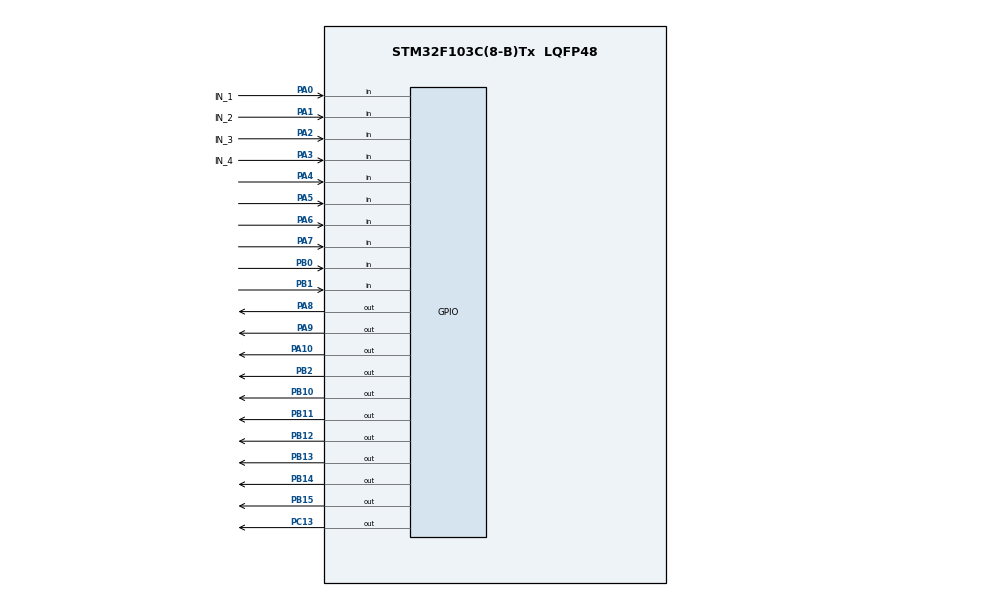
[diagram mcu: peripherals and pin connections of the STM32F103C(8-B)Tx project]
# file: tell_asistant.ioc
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Mcu.Family=STM32F1
Mcu.Name=STM32F103C(8-B)Tx
Mcu.Package=LQFP48
NVIC.PriorityGroup=NVIC_PRIORITYGROUP_4
NVIC.TIM4_IRQn=true\:0\:0\:false\:false\:true\:true
PA0-WKUP.GPIO_Label=IN_1
PA0-WKUP.GPIO_Mode=GPIO_MODE_INPUT
PA0-WKUP.GPIO_PuPd=GPIO_PULLUP
PA0-WKUP.Signal=GPIO_Input
PA1.GPIO_Label=IN_2
PA1.GPIO_Mode=GPIO_MODE_INPUT
PA1.GPIO_PuPd=GPIO_PULLUP
PA1.Signal=GPIO_Input
PA10.Signal=GPIO_Output
PA13.Mode=Serial_Wire
PA13.Signal=SYS_JTMS-SWDIO
PA14.Mode=Serial_Wire
PA14.Signal=SYS_JTCK-SWCLK
PA2.GPIO_Label=IN_3
PA2.GPIO_Mode=GPIO_MODE_INPUT
PA2.GPIO_PuPd=GPIO_PULLUP
PA2.Signal=GPIO_Input
PA3.GPIO_Label=IN_4
PA3.GPIO_Mode=GPIO_MODE_INPUT
PA3.GPIO_PuPd=GPIO_PULLUP
PA3.Signal=GPIO_Input
PA4.Signal=GPIO_Input
PA5.Signal=GPIO_Input
PA6.Signal=GPIO_Input
PA7.Signal=GPIO_Input
PA8.Signal=GPIO_Output
PA9.Signal=GPIO_Output
PB0.Signal=GPIO_Input
PB1.Signal=GPIO_Input
PB10.Signal=GPIO_Output
PB11.Signal=GPIO_Output
PB12.Signal=GPIO_Output
PB13.Signal=GPIO_Output
PB14.Signal=GPIO_Output
PB15.Signal=GPIO_Output
PB2.Signal=GPIO_Output
PC13-TAMPER-RTC.Signal=GPIO_Output
ProjectManager.HeapSize=0x200
ProjectManager.StackSize=0x400
ProjectManager.TargetToolchain=MDK-ARM V5
RCC.APB1Freq_Value=8000000
RCC.APB2Freq_Value=8000000
TIM4.AutoReloadPreload=TIM_AUTORELOAD_PRELOAD_ENABLE
TIM4.Period=1000
TIM4.Prescaler=8000
VP_TIM4_VS_ClockSourceINT.Mode=Internal
board=custom

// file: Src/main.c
/* USER CODE BEGIN Header */
/**
  ******************************************************************************
  * @file           : main.c
  * @brief          : Main program body
  ******************************************************************************
  ** This notice applies to any and all portions of this file
  * that are not between comment pairs USER CODE BEGIN and
  * USER CODE END. Other portions of this file, whether
  * inserted by the user or by software development tools
  * are owned by their respective copyright owners.
  *
  * COPYRIGHT(c) 2020 STMicroelectronics
  *
  * Redistribution and use in source and binary forms, with or without modification,
  * are permitted provided that the following conditions are met:
  *   1. Redistributions of source code must retain the above copyright notice,
  *      this list of conditions and the following disclaimer.
  *   2. Redistributions in binary form must reproduce the above copyright notice,
  *      this list of conditions and the following disclaimer in the documentation
  *      and/or other materials provided with the distribution.
  *   3. Neither the name of STMicroelectronics nor the names of its contributors
  *      may be used to endorse or promote products derived from this software
  *      without specific prior written permission.
  *
  * THIS SOFTWARE IS PROVIDED BY THE COPYRIGHT HOLDERS AND CONTRIBUTORS "AS IS"
  * AND ANY EXPRESS OR IMPLIED WARRANTIES, INCLUDING, BUT NOT LIMITED TO, THE
  * IMPLIED WARRANTIES OF MERCHANTABILITY AND FITNESS FOR A PARTICULAR PURPOSE ARE
  * DISCLAIMED. IN NO EVENT SHALL THE COPYRIGHT HOLDER OR CONTRIBUTORS BE LIABLE
  * FOR ANY DIRECT, INDIRECT, INCIDENTAL, SPECIAL, EXEMPLARY, OR CONSEQUENTIAL
  * DAMAGES (INCLUDING, BUT NOT LIMITED TO, PROCUREMENT OF SUBSTITUTE GOODS OR
  * SERVICES; LOSS OF USE, DATA, OR PROFITS; OR BUSINESS INTERRUPTION) HOWEVER
  * CAUSED AND ON ANY THEORY OF LIABILITY, WHETHER IN CONTRACT, STRICT LIABILITY,
  * OR TORT (INCLUDING NEGLIGENCE OR OTHERWISE) ARISING IN ANY WAY OUT OF THE USE
  * OF THIS SOFTWARE, EVEN IF ADVISED OF THE POSSIBILITY OF SUCH DAMAGE.
  *
  ******************************************************************************
  */
/* USER CODE END Header */

#include "main.h"

/* USER CODE BEGIN Includes */

#define led1(x) (x)?   HAL_GPIO_WritePin(OUT1_GPIO_Port,OUT1_Pin,GPIO_PIN_SET) :  HAL_GPIO_WritePin(OUT1_GPIO_Port,OUT1_Pin,GPIO_PIN_RESET)
#define led2(x) (x)?   HAL_GPIO_WritePin(OUT2_GPIO_Port,OUT2_Pin,GPIO_PIN_SET) :  HAL_GPIO_WritePin(OUT2_GPIO_Port,OUT2_Pin,GPIO_PIN_RESET)
#define led3(x) (x)?   HAL_GPIO_WritePin(OUT3_GPIO_Port,OUT3_Pin,GPIO_PIN_SET) :  HAL_GPIO_WritePin(OUT3_GPIO_Port,OUT3_Pin,GPIO_PIN_RESET)
#define led4(x) (x)?   HAL_GPIO_WritePin(OUT4_GPIO_Port,OUT4_Pin,GPIO_PIN_SET) :  HAL_GPIO_WritePin(OUT4_GPIO_Port,OUT4_Pin,GPIO_PIN_RESET)

#define in1  !HAL_GPIO_ReadPin( IN_1_GPIO_Port,IN_1_Pin )
#define in2  !HAL_GPIO_ReadPin( IN_2_GPIO_Port,IN_2_Pin )
#define in3  !HAL_GPIO_ReadPin( IN_3_GPIO_Port,IN_3_Pin )
#define in4  !HAL_GPIO_ReadPin( IN_4_GPIO_Port,IN_4_Pin )

 #define defult_time  10
/* USER CODE END Includes */

/* USER CODE BEGIN PTD */

struct TIMEING {

	public:
	int time_out_1 ;
	int time_out_2 ;
	int time_out_3 ;
	int time_out_4 ;

}tim;

struct flag
	{
	  bool flag_out_1;
	  bool flag_out_2;
	  bool flag_out_3;
	  bool flag_out_4;

  }fl;

/* USER CODE END PTD */

TIM_HandleTypeDef htim4;

void SystemClock_Config(void);
static void MX_GPIO_Init(void);
static void MX_TIM4_Init(void);

int main(void)
{

  /* MCU Configuration--------------------------------------------------------*/

  /* Reset of all peripherals, Initializes the Flash interface and the Systick. */
  HAL_Init();

  /* Configure the system clock */
  SystemClock_Config();

  /* Initialize all configured peripherals */
  MX_GPIO_Init();
  MX_TIM4_Init();
  /* USER CODE BEGIN 2 */
  HAL_TIM_Base_Start_IT(&htim4);
  /* USER CODE END 2 */

  /* Infinite loop */
  /* USER CODE BEGIN WHILE */

  while (1)
  {

		 led1( tim.time_out_1);
		 led2( tim.time_out_2);
		 led3( tim.time_out_3);
		 led4( tim.time_out_4);

		if(in1) tim.time_out_1 = defult_time;
		if(in2) tim.time_out_2 = defult_time;
		if(in3) tim.time_out_3 = defult_time;
		if(in4) tim.time_out_4 = defult_time;

    /* USER CODE END WHILE */

  }
}

void SystemClock_Config(void)
{
  RCC_OscInitTypeDef RCC_OscInitStruct = {0};
  RCC_ClkInitTypeDef RCC_ClkInitStruct = {0};

  /**Initializes the CPU, AHB and APB busses clocks
  */
  RCC_OscInitStruct.OscillatorType = RCC_OSCILLATORTYPE_HSI;
  RCC_OscInitStruct.HSIState = RCC_HSI_ON;
  RCC_OscInitStruct.HSICalibrationValue = RCC_HSICALIBRATION_DEFAULT;
  RCC_OscInitStruct.PLL.PLLState = RCC_PLL_NONE;
  if (HAL_RCC_OscConfig(&RCC_OscInitStruct) != HAL_OK)
  {
    Error_Handler();
  }
  /**Initializes the CPU, AHB and APB busses clocks
  */
  RCC_ClkInitStruct.ClockType = RCC_CLOCKTYPE_HCLK|RCC_CLOCKTYPE_SYSCLK
                              |RCC_CLOCKTYPE_PCLK1|RCC_CLOCKTYPE_PCLK2;
  RCC_ClkInitStruct.SYSCLKSource = RCC_SYSCLKSOURCE_HSI;
  RCC_ClkInitStruct.AHBCLKDivider = RCC_SYSCLK_DIV1;
  RCC_ClkInitStruct.APB1CLKDivider = RCC_HCLK_DIV1;
  RCC_ClkInitStruct.APB2CLKDivider = RCC_HCLK_DIV1;

  if (HAL_RCC_ClockConfig(&RCC_ClkInitStruct, FLASH_LATENCY_0) != HAL_OK)
  {
    Error_Handler();
  }
}

static void MX_TIM4_Init(void)
{

  TIM_ClockConfigTypeDef sClockSourceConfig = {0};
  TIM_MasterConfigTypeDef sMasterConfig = {0};

  htim4.Instance = TIM4;
  htim4.Init.Prescaler = 8000;
  htim4.Init.CounterMode = TIM_COUNTERMODE_UP;
  htim4.Init.Period = 1000;
  htim4.Init.ClockDivision = TIM_CLOCKDIVISION_DIV1;
  htim4.Init.AutoReloadPreload = TIM_AUTORELOAD_PRELOAD_ENABLE;
  if (HAL_TIM_Base_Init(&htim4) != HAL_OK)
  {
    Error_Handler();
  }
  sClockSourceConfig.ClockSource = TIM_CLOCKSOURCE_INTERNAL;
  if (HAL_TIM_ConfigClockSource(&htim4, &sClockSourceConfig) != HAL_OK)
  {
    Error_Handler();
  }
  sMasterConfig.MasterOutputTrigger = TIM_TRGO_RESET;
  sMasterConfig.MasterSlaveMode = TIM_MASTERSLAVEMODE_DISABLE;
  if (HAL_TIMEx_MasterConfigSynchronization(&htim4, &sMasterConfig) != HAL_OK)
  {
    Error_Handler();
  }

}

static void MX_GPIO_Init(void)
{
  GPIO_InitTypeDef GPIO_InitStruct = {0};

  /* GPIO Ports Clock Enable */
  __HAL_RCC_GPIOC_CLK_ENABLE();
  __HAL_RCC_GPIOA_CLK_ENABLE();
  __HAL_RCC_GPIOB_CLK_ENABLE();

  /*Configure GPIO pin Output Level */
  HAL_GPIO_WritePin(GPIOC, GPIO_PIN_13, GPIO_PIN_RESET);

  /*Configure GPIO pin Output Level */
  HAL_GPIO_WritePin(GPIOB, OUT1_Pin|OUT2_Pin|OUT3_Pin|OUT4_Pin, GPIO_PIN_RESET);

  /*Configure GPIO pin : PC13 */
  GPIO_InitStruct.Pin = GPIO_PIN_13;
  GPIO_InitStruct.Mode = GPIO_MODE_OUTPUT_PP;
  GPIO_InitStruct.Pull = GPIO_NOPULL;
  GPIO_InitStruct.Speed = GPIO_SPEED_FREQ_LOW;
  HAL_GPIO_Init(GPIOC, &GPIO_InitStruct);

  /*Configure GPIO pins : IN_1_Pin IN_2_Pin IN_3_Pin IN_4_Pin */
  GPIO_InitStruct.Pin = IN_1_Pin|IN_2_Pin|IN_3_Pin|IN_4_Pin;
  GPIO_InitStruct.Mode = GPIO_MODE_INPUT;
  GPIO_InitStruct.Pull = GPIO_PULLUP;
  HAL_GPIO_Init(GPIOA, &GPIO_InitStruct);

  /*Configure GPIO pins : OUT1_Pin OUT2_Pin OUT3_Pin OUT4_Pin */
  GPIO_InitStruct.Pin = OUT1_Pin|OUT2_Pin|OUT3_Pin|OUT4_Pin;
  GPIO_InitStruct.Mode = GPIO_MODE_OUTPUT_PP;
  GPIO_InitStruct.Pull = GPIO_NOPULL;
  GPIO_InitStruct.Speed = GPIO_SPEED_FREQ_LOW;
  HAL_GPIO_Init(GPIOB, &GPIO_InitStruct);

}

/* USER CODE BEGIN 4 */
void HAL_TIM_PeriodElapsedCallback(TIM_HandleTypeDef *htim)
{

 if( htim->Instance == TIM4 )  // 1000 ms
 {
   if(tim.time_out_1) tim.time_out_1--;
   if(tim.time_out_2) tim.time_out_2--;
	 if(tim.time_out_3) tim.time_out_3--;
	 if(tim.time_out_4) tim.time_out_4--;
 }

};

/* USER CODE END 4 */

void Error_Handler(void)
{
}

/************************ (C) COPYRIGHT STMicroelectronics *****END OF FILE****/
